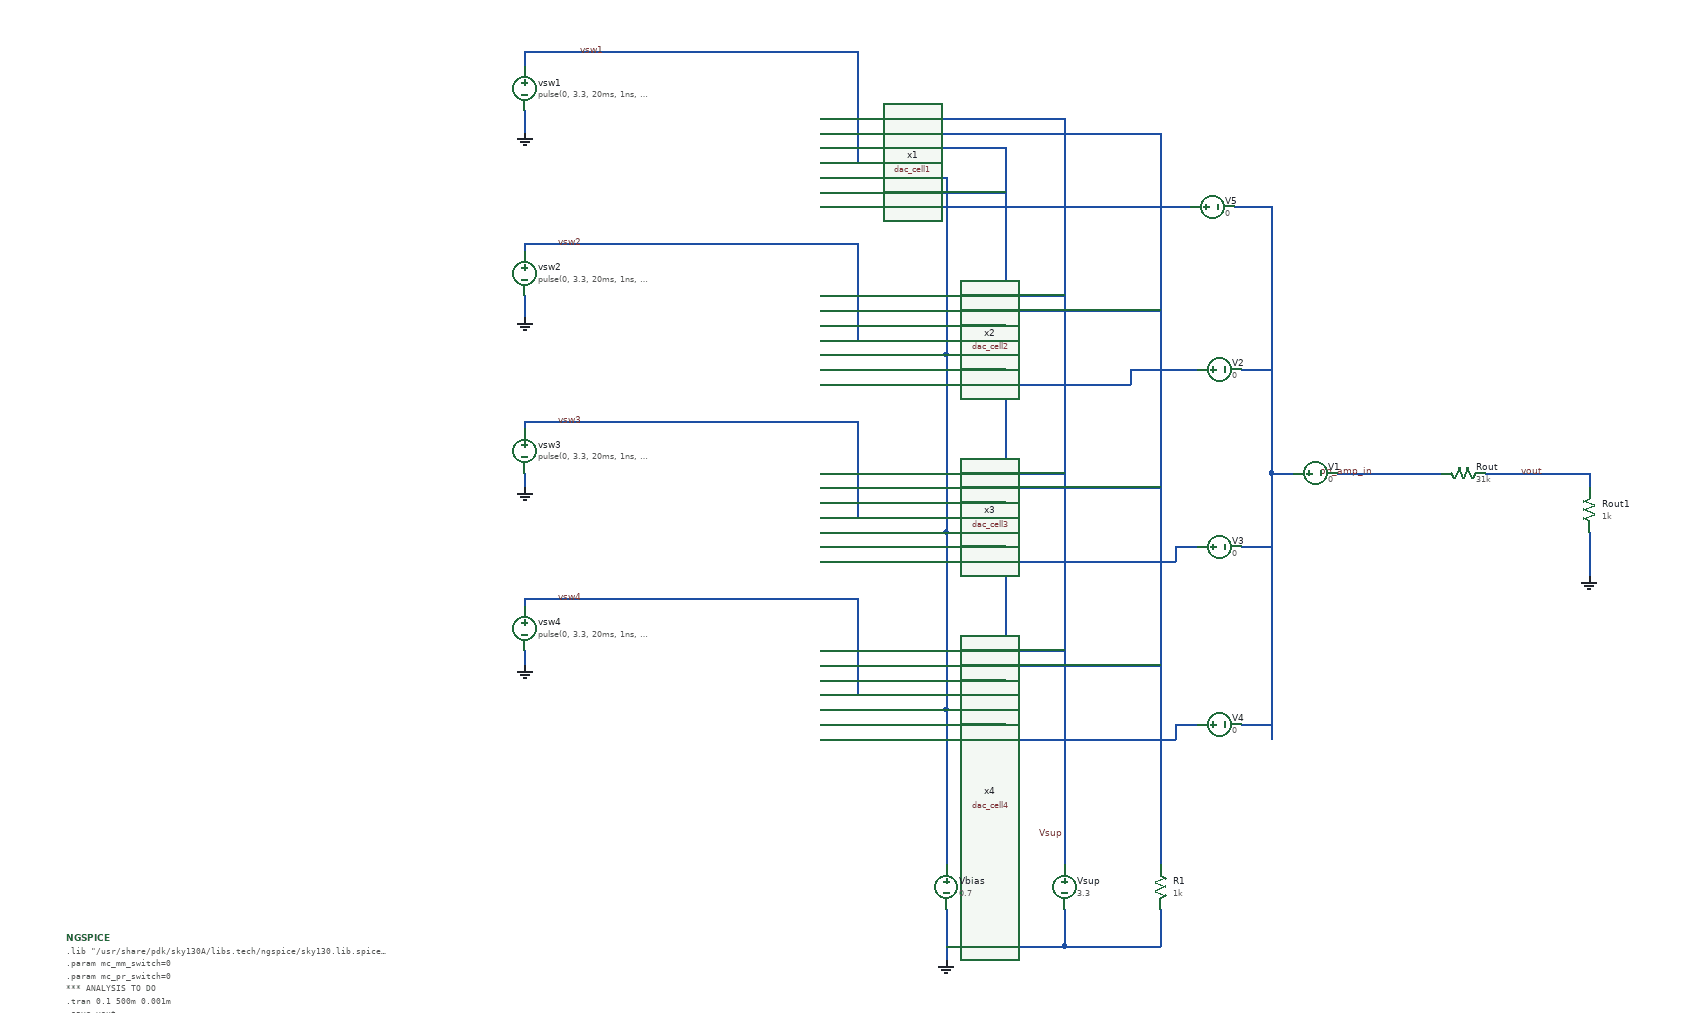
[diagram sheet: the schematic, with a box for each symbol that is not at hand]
v {xschem version=2.9.9 file_version=1.2 }
G {}
K {}
V {}
S {}
E {}
N 1680 -1150 1680 -940 { lab=#net1}
N 1510 -1150 1680 -1150 { lab=#net1}
N 1510 -1390 1680 -1390 { lab=#net1}
N 1680 -1390 1680 -1150 { lab=#net1}
N 1680 -1630 1680 -1390 { lab=#net1}
N 1510 -1630 1680 -1630 { lab=#net1}
N 1680 -1860 1680 -1630 { lab=#net1}
N 1680 -1870 1680 -1860 { lab=#net1}
N 1510 -1870 1680 -1870 { lab=#net1}
N 1680 -870 1680 -810 { lab=GND}
N 1680 -830 1760 -830 { lab=GND}
N 1760 -1890 1760 -830 { lab=GND}
N 1510 -1910 1760 -1910 { lab=GND}
N 1760 -1910 1760 -1890 { lab=GND}
N 1510 -1670 1760 -1670 { lab=GND}
N 1510 -1430 1760 -1430 { lab=GND}
N 1510 -1190 1760 -1190 { lab=GND}
N 1680 -880 1680 -870 { lab=GND}
N 1840 -880 1840 -830 { lab=GND}
N 1760 -830 1840 -830 { lab=GND}
N 1840 -1950 1840 -940 { lab=Vsup}
N 1510 -1950 1840 -1950 { lab=Vsup}
N 1510 -1710 1840 -1710 { lab=Vsup}
N 1510 -1470 1840 -1470 { lab=Vsup}
N 1510 -1230 1840 -1230 { lab=Vsup}
N 1970 -880 1970 -830 { lab=GND}
N 1840 -830 1970 -830 { lab=GND}
N 1970 -1930 1970 -940 { lab=#net2}
N 1510 -1930 1970 -1930 { lab=#net2}
N 1510 -1690 1970 -1690 { lab=#net2}
N 1510 -1450 1970 -1450 { lab=#net2}
N 1510 -1210 1970 -1210 { lab=#net2}
N 2220 -1470 2350 -1470 { lab=op_amp_in}
N 2410 -1470 2550 -1470 { lab=vout}
N 1560 -2000 1560 -1890 { lab=vsw1}
N 1510 -1890 1560 -1890 { lab=vsw1}
N 1560 -1760 1560 -1650 { lab=vsw2}
N 1510 -1650 1560 -1650 { lab=vsw2}
N 1560 -1520 1560 -1410 { lab=vsw3}
N 1510 -1410 1560 -1410 { lab=vsw3}
N 1560 -1280 1560 -1170 { lab=vsw4}
N 1510 -1170 1560 -1170 { lab=vsw4}
N 1560 -2040 1560 -2000 { lab=vsw1}
N 1110 -2040 1560 -2040 { lab=vsw1}
N 1110 -2040 1110 -2020 { lab=vsw1}
N 1110 -1780 1110 -1770 { lab=vsw2}
N 1110 -1780 1560 -1780 { lab=vsw2}
N 1560 -1780 1560 -1760 { lab=vsw2}
N 1110 -1540 1110 -1530 { lab=vsw3}
N 1110 -1540 1560 -1540 { lab=vsw3}
N 1560 -1540 1560 -1520 { lab=vsw3}
N 1110 -1300 1110 -1290 { lab=vsw4}
N 1110 -1300 1560 -1300 { lab=vsw4}
N 1560 -1300 1560 -1280 { lab=vsw4}
N 1110 -1470 1110 -1450 { lab=GND}
N 1110 -1230 1110 -1210 { lab=GND}
N 1110 -1710 1110 -1680 { lab=GND}
N 1110 -1960 1110 -1930 { lab=GND}
N 2120 -1820 2120 -1470 { lab=#net3}
N 2120 -1470 2120 -1350 { lab=#net3}
N 2120 -1350 2120 -1110 { lab=#net3}
N 2550 -1470 2550 -1450 { lab=vout}
N 2550 -1390 2550 -1330 { lab=GND}
N 2210 -1470 2220 -1470 { lab=op_amp_in}
N 2120 -1470 2150 -1470 { lab=#net3}
N 2080 -1130 2120 -1130 { lab=#net3}
N 2080 -1370 2120 -1370 { lab=#net3}
N 2080 -1610 2120 -1610 { lab=#net3}
N 1510 -1850 1760 -1850 { lab=GND}
N 1510 -1610 1760 -1610 { lab=GND}
N 1510 -1590 1930 -1590 { lab=#net4}
N 1930 -1610 1930 -1590 { lab=#net4}
N 1930 -1610 2020 -1610 { lab=#net4}
N 1510 -1370 1760 -1370 { lab=GND}
N 1510 -1350 1990 -1350 { lab=#net5}
N 1990 -1370 1990 -1350 { lab=#net5}
N 1990 -1370 2020 -1370 { lab=#net5}
N 1510 -1110 1990 -1110 { lab=#net6}
N 1990 -1130 1990 -1110 { lab=#net6}
N 1990 -1130 2020 -1130 { lab=#net6}
N 1510 -1130 1760 -1130 { lab=GND}
N 1510 -1830 2010 -1830 { lab=#net7}
N 2070 -1830 2120 -1830 { lab=#net3}
N 2120 -1830 2120 -1820 { lab=#net3}
C {/opt/uniccass/dev/dac_cell1/tb/dac_cell1.sym} 1360 -1890 0 0 {name=x1}
C {/opt/uniccass/dev/dac_cell2/tb/dac_cell2.sym} 1360 -1650 0 0 {name=x2}
C {/opt/uniccass/dev/dac_cell3/tb/dac_cell3.sym} 1360 -1410 0 0 {name=x3}
C {/opt/uniccass/dev/dac_cell4/tb/dac_cell4.sym} 1360 -1170 0 0 {name=x4}
C {devices/vsource.sym} 1110 -1990 0 0 {name=vsw1 value="pulse(0, 3.3, 20ms, 1ns, 1ns, 10ms, 20ms)"}
C {devices/vsource.sym} 1110 -1740 0 0 {name=vsw2 value="pulse(0, 3.3, 20ms, 1ns, 1ns, 20ms, 40ms)"}
C {devices/vsource.sym} 1110 -1500 0 0 {name=vsw3 value="pulse(0, 3.3, 20ms, 1ns, 1ns, 40ms, 80ms)"}
C {devices/vsource.sym} 1110 -1260 0 0 {name=vsw4 value="pulse(0, 3.3, 20ms, 1ns, 1ns, 80ms, 160ms)"}
C {devices/gnd.sym} 1110 -1210 0 0 {name=l4 lab=GND}
C {devices/gnd.sym} 1110 -1450 0 0 {name=l5 lab=GND}
C {devices/gnd.sym} 1110 -1680 0 0 {name=l6 lab=GND}
C {devices/gnd.sym} 1110 -1930 0 0 {name=l7 lab=GND}
C {devices/gnd.sym} 1680 -810 0 0 {name=l1 lab=GND}
C {devices/res.sym} 1970 -910 0 0 {name=R1
value=1k
footprint=1206
device=resistor
m=1}
C {devices/vsource.sym} 1840 -910 0 0 {name=Vsup value=3.3}
C {devices/vsource.sym} 1680 -910 0 0 {name=Vbias value=0.7}
C {devices/res.sym} 2380 -1470 1 0 {name=Rout
value=31k
footprint=1206
device=resistor
m=1}
C {devices/lab_wire.sym} 2260 -1470 1 0 {name=l2 sig_type=std_logic lab=op_amp_in}
C {devices/lab_wire.sym} 1840 -980 0 0 {name=l3 sig_type=std_logic lab=Vsup}
C {devices/code_shown.sym} 490 -840 0 0 {name=NGSPICE
only_toplevel=true
value="
.lib \\"/usr/share/pdk/sky130A/libs.tech/ngspice/sky130.lib.spice\\" tt
.param mc_mm_switch=0
.param mc_pr_switch=0
*** ANALYSIS TO DO

.tran 0.1 500m 0.001m
.save vout
.save i(V1)
.save i(V2)
.save i(V3)
.save i(V4)
.save i(V5)
.save vsw1 vsw2 vsw3 vsw4

.control
set wr_vecnames
set wr_singlescale

run
******** results filename  ************ nodes to write
wrdata $DEV_PATH/res/dac_top_cell_vout_tran_vol.res vout
wrdata $DEV_PATH/res/dac_top_cell_vsw1_tran_vol.res vsw1
wrdata $DEV_PATH/res/dac_top_cell_vsw2_tran_vol.res vsw2
wrdata $DEV_PATH/res/dac_top_cell_vsw3_tran_vol.res vsw3
wrdata $DEV_PATH/res/dac_top_cell_vsw4_tran_vol.res vsw4
.endc
"}
C {devices/lab_wire.sym} 1220 -2040 1 0 {name=l8 sig_type=std_logic lab=vsw1}
C {devices/lab_wire.sym} 1190 -1780 1 0 {name=l9 sig_type=std_logic lab=vsw2}
C {devices/lab_wire.sym} 1190 -1540 1 0 {name=l10 sig_type=std_logic lab=vsw3}
C {devices/lab_wire.sym} 1190 -1300 1 0 {name=l11 sig_type=std_logic lab=vsw4}
C {devices/gnd.sym} 2550 -1330 0 0 {name=l12 lab=GND}
C {devices/lab_wire.sym} 2490 -1470 1 0 {name=l13 sig_type=std_logic lab=vout}
C {devices/res.sym} 2550 -1420 2 0 {name=Rout1
value=1k
footprint=1206
device=resistor
m=1}
C {devices/vsource.sym} 2180 -1470 3 0 {name=V1 value=0}
C {devices/vsource.sym} 2050 -1610 3 0 {name=V2 value=0}
C {devices/vsource.sym} 2050 -1370 3 0 {name=V3 value=0}
C {devices/vsource.sym} 2050 -1130 3 0 {name=V4 value=0}
C {devices/vsource.sym} 2040 -1830 3 0 {name=V5 value=0}
